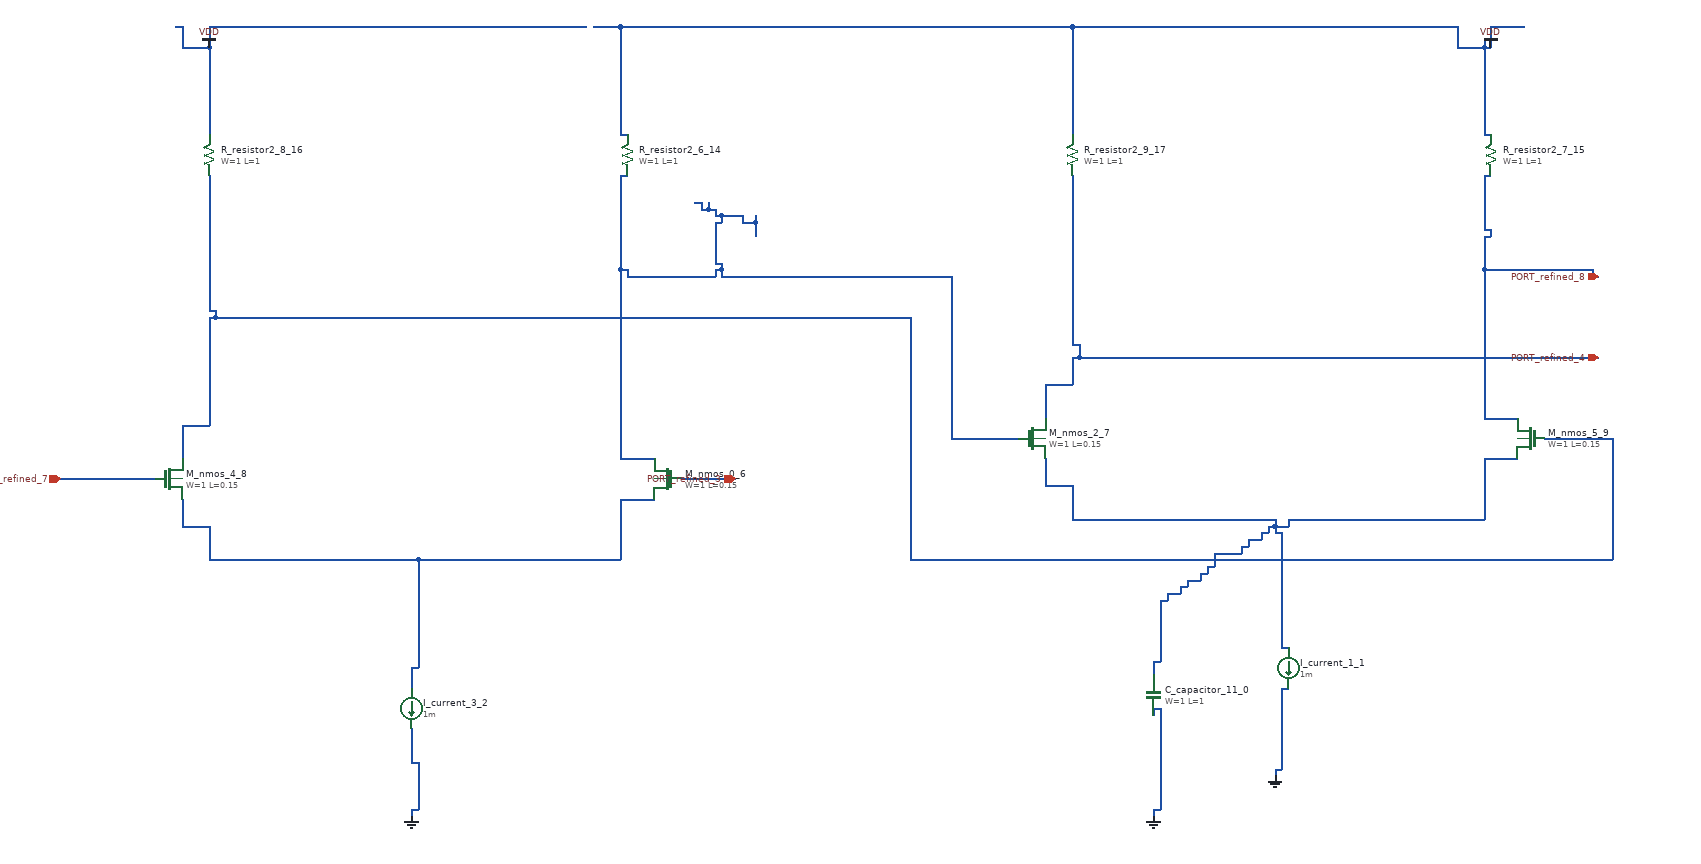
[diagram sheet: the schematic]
v {xschem version=3.4.8 file_version=1.2}
G {}
K {}
V {}
S {}
E {}
C {sky130_fd_pr/cap_mim_m3_1.sym} 1700 1200 0 0 {name="C_capacitor_11_0" model=cap_mim_m3_1 W=1 L=1 MF=1 spiceprefix=X}
C {devices/isource.sym} 1900 1160 0 0 {name="I_current_1_1" value=1m}
C {devices/isource.sym} 600 1220 0 0 {name="I_current_3_2" value=1m}
C {devices/gnd.sym} 1700 1380 0 0 {name="l_gnd_10_3" lab="GND"}
C {devices/gnd.sym} 600 1380 0 0 {name="l_gnd_12_4" lab="GND"}
C {devices/gnd.sym} 1880 1320 0 0 {name="l_gnd_13_5" lab="GND"}
C {sky130_fd_pr/nfet3_01v8.sym} 980 880 0 1 {name="M_nmos_0_6"
W=1
L=0.15
body=GND
nf=1
mult=1
ad="expr('int((@nf + 1)/2) * @W / @nf * 0.29')"
pd="expr('2*int((@nf + 1)/2) * (@W / @nf + 0.29)')"
as="expr('int((@nf + 2)/2) * @W / @nf * 0.29')"
ps="expr('2*int((@nf + 2)/2) * (@W / @nf + 0.29)')"
nrd="expr('0.29 / @W ')" nrs="expr('0.29 / @W ')"
sa=0 sb=0 sd=0
model=nfet_01v8
spiceprefix=X
}
C {sky130_fd_pr/nfet3_01v8.sym} 1520 820 0 0 {name="M_nmos_2_7"
W=1
L=0.15
body=GND
nf=1
mult=1
ad="expr('int((@nf + 1)/2) * @W / @nf * 0.29')"
pd="expr('2*int((@nf + 1)/2) * (@W / @nf + 0.29)')"
as="expr('int((@nf + 2)/2) * @W / @nf * 0.29')"
ps="expr('2*int((@nf + 2)/2) * (@W / @nf + 0.29)')"
nrd="expr('0.29 / @W ')" nrs="expr('0.29 / @W ')"
sa=0 sb=0 sd=0
model=nfet_01v8
spiceprefix=X
}
C {sky130_fd_pr/nfet3_01v8.sym} 240 880 0 0 {name="M_nmos_4_8"
W=1
L=0.15
body=GND
nf=1
mult=1
ad="expr('int((@nf + 1)/2) * @W / @nf * 0.29')"
pd="expr('2*int((@nf + 1)/2) * (@W / @nf + 0.29)')"
as="expr('int((@nf + 2)/2) * @W / @nf * 0.29')"
ps="expr('2*int((@nf + 2)/2) * (@W / @nf + 0.29)')"
nrd="expr('0.29 / @W ')" nrs="expr('0.29 / @W ')"
sa=0 sb=0 sd=0
model=nfet_01v8
spiceprefix=X
}
C {sky130_fd_pr/nfet3_01v8.sym} 2260 820 0 1 {name="M_nmos_5_9"
W=1
L=0.15
body=GND
nf=1
mult=1
ad="expr('int((@nf + 1)/2) * @W / @nf * 0.29')"
pd="expr('2*int((@nf + 1)/2) * (@W / @nf + 0.29)')"
as="expr('int((@nf + 2)/2) * @W / @nf * 0.29')"
ps="expr('2*int((@nf + 2)/2) * (@W / @nf + 0.29)')"
nrd="expr('0.29 / @W ')" nrs="expr('0.29 / @W ')"
sa=0 sb=0 sd=0
model=nfet_01v8
spiceprefix=X
}
C {devices/ipin.sym} 2360 580 0 0 {name="p_port_14_10" lab="PORT_refined_8"}
C {devices/ipin.sym} 2360 700 0 0 {name="p_port_15_11" lab="PORT_refined_4"}
C {devices/ipin.sym} 1080 880 0 0 {name="p_port_20_12" lab="PORT_refined_3"}
C {devices/ipin.sym} 80 880 0 0 {name="p_port_22_13" lab="PORT_refined_7"}
C {sky130_fd_pr/res_generic_po.sym} 920 400 2 0 {name="R_resistor2_6_14"
W=1
L=1
model=res_generic_po
spiceprefix=X
mult=1}
C {sky130_fd_pr/res_generic_po.sym} 2200 400 2 0 {name="R_resistor2_7_15"
W=1
L=1
model=res_generic_po
spiceprefix=X
mult=1}
C {sky130_fd_pr/res_generic_po.sym} 300 400 2 0 {name="R_resistor2_8_16"
W=1
L=1
model=res_generic_po
spiceprefix=X
mult=1}
C {sky130_fd_pr/res_generic_po.sym} 1580 400 2 0 {name="R_resistor2_9_17"
W=1
L=1
model=res_generic_po
spiceprefix=X
mult=1}
C {devices/vdd.sym} 2200 240 0 0 {name="l_vdd_16_18" lab="VDD"}
C {devices/vdd.sym} 300 240 0 0 {name="l_vdd_17_19" lab="VDD"}
N 600 1370 610 1370 {}
N 1700 1370 1710 1370 {}
N 1880 1310 1890 1310 {}
N 600 1300 610 1300 {}
N 1700 1220 1710 1220 {}
N 1890 1190 1900 1190 {}
N 600 1380 600 1370 {}
N 600 1300 600 1250 {}
N 610 1370 610 1300 {}
N 1700 1380 1700 1370 {}
N 1700 1230 1700 1220 {}
N 1710 1370 1710 1220 {}
N 1880 1320 1880 1310 {}
N 1890 1310 1890 1190 {}
N 1700 1150 1710 1150 {}
N 1890 1130 1900 1130 {}
N 1710 1060 1720 1060 {}
N 1720 1050 1740 1050 {}
N 1740 1040 1750 1040 {}
N 1750 1030 1770 1030 {}
N 1770 1020 1780 1020 {}
N 1780 1010 1790 1010 {}
N 1790 990 1830 990 {}
N 1830 980 1840 980 {}
N 1840 970 1860 970 {}
N 1860 960 1870 960 {}
N 1880 960 1890 960 {}
N 1870 950 1880 950 {}
N 1880 950 1900 950 {}
N 1580 940 1880 940 {}
N 1900 940 2190 940 {}
N 1540 890 1580 890 {}
N 2190 850 2240 850 {}
N 1540 890 1540 850 {}
N 1580 940 1580 890 {}
N 1700 1170 1700 1150 {}
N 1710 1150 1710 1060 {}
N 1720 1060 1720 1050 {}
N 1740 1050 1740 1040 {}
N 1750 1040 1750 1030 {}
N 1770 1030 1770 1020 {}
N 1780 1020 1780 1010 {}
N 1790 1010 1790 990 {}
N 1830 990 1830 980 {}
N 1840 980 1840 970 {}
N 1860 970 1860 960 {}
N 1870 960 1870 950 {}
N 1880 960 1880 950 {}
N 1880 950 1880 940 {}
N 1890 1130 1890 960 {}
N 1900 950 1900 940 {}
N 2190 940 2190 850 {}
N 910 850 960 850 {}
N 1400 820 1500 820 {}
N 920 580 1050 580 {}
N 1060 580 1400 580 {}
N 910 570 920 570 {}
N 1050 570 1060 570 {}
N 1050 560 1060 560 {}
N 1050 500 1060 500 {}
N 1090 500 1110 500 {}
N 1050 490 1060 490 {}
N 1060 490 1090 490 {}
N 1030 480 1040 480 {}
N 1040 480 1050 480 {}
N 1020 470 1030 470 {}
N 910 430 920 430 {}
N 910 850 910 570 {}
N 910 570 910 430 {}
N 920 580 920 570 {}
N 1030 480 1030 470 {}
N 1040 480 1040 470 {}
N 1050 580 1050 570 {}
N 1050 560 1050 500 {}
N 1050 490 1050 480 {}
N 1060 580 1060 570 {}
N 1060 570 1060 560 {}
N 1060 500 1060 490 {}
N 1090 500 1090 490 {}
N 1110 520 1110 500 {}
N 1110 500 1110 490 {}
N 1400 820 1400 580 {}
N 1000 880 1080 880 {}
N 1540 740 1580 740 {}
N 1580 700 1590 700 {}
N 1590 700 2360 700 {}
N 1580 680 1590 680 {}
N 1540 790 1540 740 {}
N 1580 740 1580 700 {}
N 1580 680 1580 430 {}
N 1590 700 1590 680 {}
N 1340 1000 2380 1000 {}
N 2280 820 2380 820 {}
N 260 800 300 800 {}
N 300 640 310 640 {}
N 310 640 1340 640 {}
N 300 630 310 630 {}
N 260 850 260 800 {}
N 300 800 300 640 {}
N 300 630 300 430 {}
N 310 640 310 630 {}
N 1340 1000 1340 640 {}
N 2380 1000 2380 820 {}
N 600 1160 610 1160 {}
N 300 1000 610 1000 {}
N 610 1000 910 1000 {}
N 260 950 300 950 {}
N 910 910 960 910 {}
N 260 950 260 910 {}
N 300 1000 300 950 {}
N 600 1190 600 1160 {}
N 610 1160 610 1000 {}
N 910 1000 910 910 {}
N 80 880 220 880 {}
N 2190 790 2240 790 {}
N 2350 580 2360 580 {}
N 2190 570 2350 570 {}
N 2190 520 2200 520 {}
N 2190 510 2200 510 {}
N 2190 430 2200 430 {}
N 2190 790 2190 570 {}
N 2190 570 2190 520 {}
N 2190 510 2190 430 {}
N 2200 520 2200 510 {}
N 2350 580 2350 570 {}
N 910 370 920 370 {}
N 2190 370 2200 370 {}
N 260 240 300 240 {}
N 2150 240 2190 240 {}
N 2190 240 2200 240 {}
N 250 210 260 210 {}
N 300 210 860 210 {}
N 870 210 910 210 {}
N 910 210 1580 210 {}
N 1580 210 2150 210 {}
N 2200 210 2250 210 {}
N 260 240 260 210 {}
N 300 370 300 240 {}
N 300 240 300 210 {}
N 910 370 910 210 {}
N 1580 370 1580 210 {}
N 2150 240 2150 210 {}
N 2190 370 2190 240 {}
N 2190 240 2190 230 {}
N 2200 240 2200 210 {}
